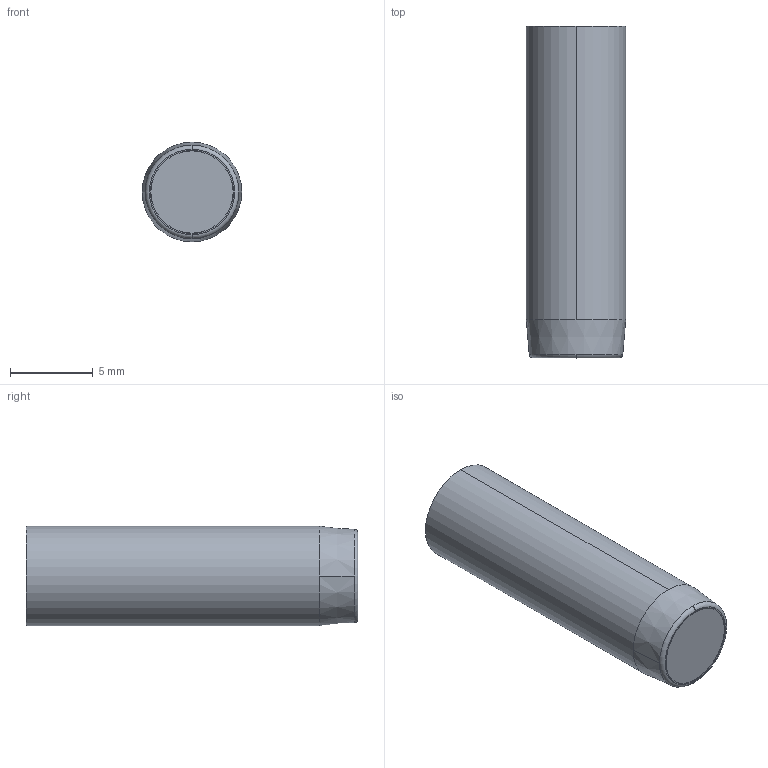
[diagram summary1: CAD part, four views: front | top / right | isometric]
STEP (ISO 10303-21) file: header records copied from the file, then geometry measured from it (millimetres).
FILE_DESCRIPTION (( 'STEP AP214' ), '1' );
FILE_NAME ('FA 063212-21.STEP', '2020-08-11T08:44:56', ( '' ), ( '' ), 'SwSTEP 2.0', 'SolidWorks 2019', '' );
FILE_SCHEMA (( 'AUTOMOTIVE_DESIGN' ));
Length unit declared in the file: millimetre
Products named in the file (6): 9FA 063212; IA 321714; FA 063200-3; FA 063200-2 - comprimido; FA 063212-21; FA 063200-1
Assembly tree (5 placements, depth 2):
  FA 063212-21
    9FA 063212
    FA 063200-1
    IA 321714
    FA 063200-3
    FA 063200-2 - comprimido
Bounding box: 6 x 20 x 6 mm (x, y, z)
Volume: 469.9 mm3; surface area: 1126.7 mm2
Topology: 5 solids, 5 shells, 328 faces, 839 edges, 549 vertices
Faces by surface type: plane 151, cylinder 132, cone 22, bspline 13, torus 10
Entity records: 12551 total; most frequent: CARTESIAN_POINT 4155, DIRECTION 1737, ORIENTED_EDGE 1674, EDGE_CURVE 837, AXIS2_PLACEMENT_3D 635, VERTEX_POINT 549, LINE 467, VECTOR 467
One B-rep face of a CAD part: STEP entity #4204.
In plain terms, the planar face has unit normal (0, -1, 0).
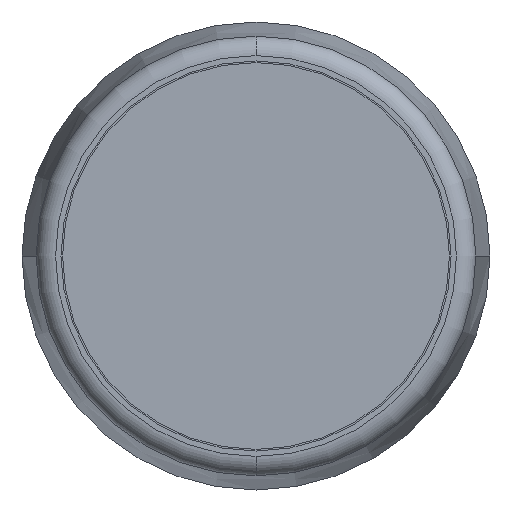
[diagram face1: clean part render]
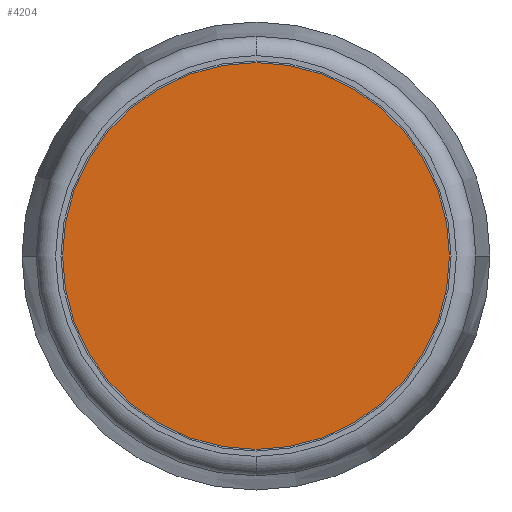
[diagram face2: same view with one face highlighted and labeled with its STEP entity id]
Its self-contained STEP definition (entity closure, numbers rounded to 3 decimals):
#577 = AXIS2_PLACEMENT_3D ( 'NONE', #5557, #4714, #5610 ) ;
#841 = CARTESIAN_POINT ( 'NONE',  ( -2.562, 0.15, -10. ) ) ;
#1305 = CARTESIAN_POINT ( 'NONE',  ( 0., 0.15, -2.5 ) ) ;
#1383 = CARTESIAN_POINT ( 'NONE',  ( 0., 0.15, 2.5 ) ) ;
#1389 = EDGE_CURVE ( 'NONE', #4619, #10249, #6090, .T. ) ;
#2657 = DIRECTION ( 'NONE',  ( 0., 1., 0. ) ) ;
#4204 = ADVANCED_FACE ( 'NONE', ( #5693 ), #9567, .F. ) ;
#4619 = VERTEX_POINT ( 'NONE', #1383 ) ;
#4714 = DIRECTION ( 'NONE',  ( 0., 1., 0. ) ) ;
#5445 = EDGE_LOOP ( 'NONE', ( #10025, #7103 ) ) ;
#5557 = CARTESIAN_POINT ( 'NONE',  ( 0., 0.15, 0. ) ) ;
#5610 = DIRECTION ( 'NONE',  ( 0., 0., 1. ) ) ;
#5653 = CARTESIAN_POINT ( 'NONE',  ( 0., 0.15, 0. ) ) ;
#5693 = FACE_OUTER_BOUND ( 'NONE', #5445, .T. ) ;
#5885 = AXIS2_PLACEMENT_3D ( 'NONE', #5653, #2657, #11508 ) ;
#6090 = CIRCLE ( 'NONE', #577, 2.5 ) ;
#7103 = ORIENTED_EDGE ( 'NONE', *, *, #8556, .F. ) ;
#8556 = EDGE_CURVE ( 'NONE', #10249, #4619, #10991, .T. ) ;
#8626 = DIRECTION ( 'NONE',  ( 0., 1., 0. ) ) ;
#9391 = AXIS2_PLACEMENT_3D ( 'NONE', #841, #8626, #12513 ) ;
#9567 = PLANE ( 'NONE',  #9391 ) ;
#10025 = ORIENTED_EDGE ( 'NONE', *, *, #1389, .F. ) ;
#10249 = VERTEX_POINT ( 'NONE', #1305 ) ;
#10991 = CIRCLE ( 'NONE', #5885, 2.5 ) ;
#11508 = DIRECTION ( 'NONE',  ( 0., 0., 1. ) ) ;
#12513 = DIRECTION ( 'NONE',  ( 0., 0., 1. ) ) ;
